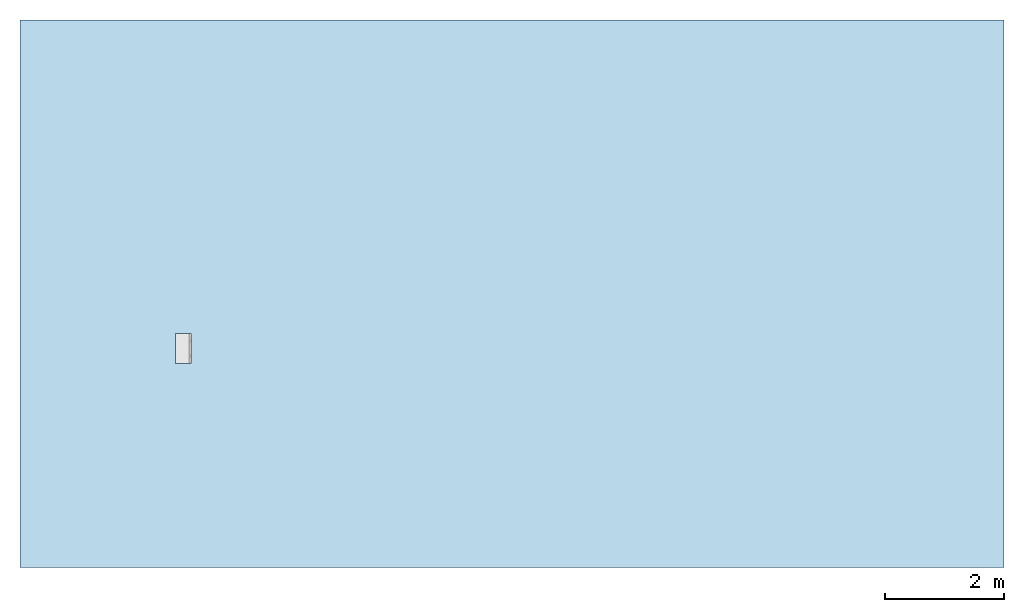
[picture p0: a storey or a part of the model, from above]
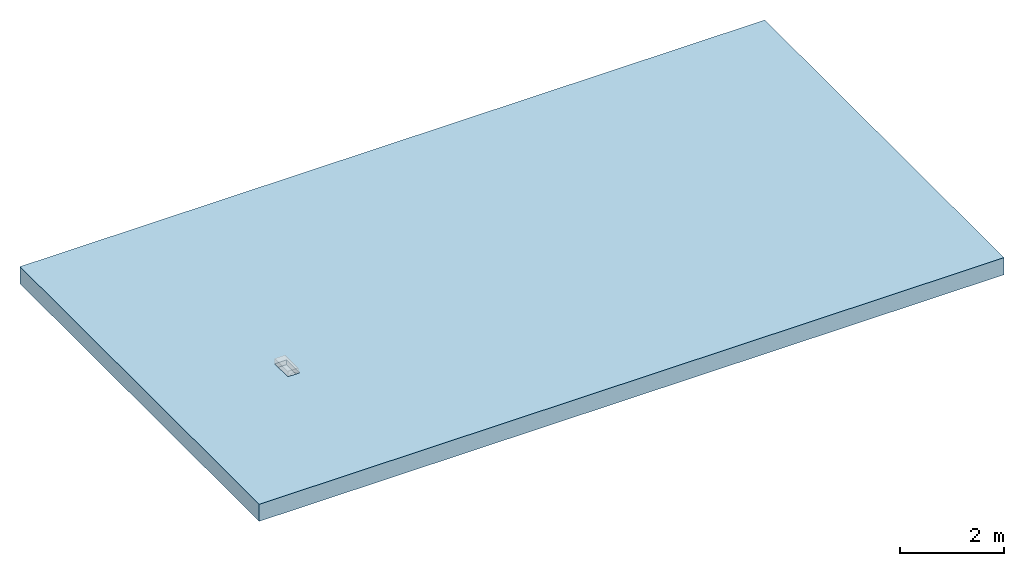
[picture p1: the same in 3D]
Properties of the parts of a building model (IFC2X3)

# File
Description: ViewDefinition [CoordinationView]
File name: T0132 - Channel - 500mm LG - 235mm High.ifc
Time: 2013-09-04T09:02:52
Written by: Autodesk Revit 2013
Made in: 20120221_2030(x64)

# IfcProject, Project Number
LongName: Project Name; Phase: Project Status

# IfcSite, Default
RefLatitude: 42, 21, 30, 344238; RefLongitude: -71, -3, -35, -194702; RefElevation: 0 mm

# IfcBuilding
Pset_BuildingCommon - NumberOfStoreys: 1
Other - Project Address: ## Street City, State Zip; Project Number: Project Number; Client Name: Owner; Project Status: Project Status; Project Issue Date: Issue Date; Project Name: Project Name

# IfcBuildingStorey, Level 1
LongName: Level 1; Elevation: 0 mm
Graphics - Symbol at End 2 Default: yes; Symbol: M_Level Head - Circle: M_Level Head - Circle; Line Pattern: Center; Symbol at End 1 Default: no; Line Weight: 1; Color: 0
Constraints - Elevation Base: 0; Elevation: 0 mm
Identity Data - Name: Level 1; Structural: no; Building Story: yes
Dimensions - Computation Height: 0 mm

# IfcBuildingElementProxy: T0132 - Channel - 500mm LG - 235mm High, Civil-Drainage-Channel-ACO-KerbDrain-KD200:T0132 - Channel - 500mm LG - 235mm High:T0132 - Channel - 500mm LG - 235mm High:308203
In: Level 1
Material: ACO Polymer Concrete.
Phasing - Phase Created: New Construction
Dimensions - Volume: 18537256 mm3; Void Depth.: -110 mm; Void length: 500 mm
Constraints - Level: Level: Level 1; Moves With Nearby Elements: no
Pset_BuildingElementProxyCommon - Reference: T0132 - Channel - 500mm LG - 235mm High
Green Building Properties - Channel Recyclable: Fully recyclable; Access Cover/Frame Recyclable: N/A; Channel Recycled Material Content: 20% minimum; Access Cover/Frame Recycled Material Content: N/A; End Cap Recyclable: N/A; End Cap Recycled Material Content: N/A
Identity Data - Product brochure: http://www.aco.co.uk/download.php?id=120; Type Comments: ACO KerbDrain KD200 half battered kerb unit 235 high 500mm long; OmniClass Number: 23.70.50.24; Assembly Description: Rain Water Drainage; Fax: +44 (0)1462 815895; Price: POA - contact ACO; Address: ACO Business Park, Hitchin Road, Shefford, Bedfordshire, United Kingdom SG17 5TE; OmniClass Title: Rainwater Removal; Model: ACO KerbDrain KD200; Manufacturer: ACO Technologies plc - ACO Water Management Division; Cost: 0; Assembly Code: D2040; e-mail Sales: customersupport@aco.co.uk; Product Page URL: http://www.aco.co.uk/product_detail.php?id=3; Telephone: +44 (0)1462 816666; Maintenance guidelines: http://www.aco.co.uk/download.php?id=120; URL: www.aco.co.uk; Installation guidelines: http://www.aco.co.uk/download.php?id=120; Model Description: Combined kerb and drainage system; Product Code: T0132; e-mail Technical: technical@aco.co.uk
General - TagNumber: 0.000000; SerialNumber: 0.000000
Materials and Finishes - Channel Colour: Grey; Access Cover/Frame Material: N/A; End Cap Colour: N/A; Channel Material: Vienite® Synthetic Resin Concrete; Access Cover/Frame Colour: N/A; End Cap Material: N/A; Access Cover/Frame Finish: N/A
Data - Concrete Surround Volume - Load Class A 15 - D 400 - Concrete Pavement: 0.20m³/m; ACO Hydraulic Design Software: http://www.acodesign.co.uk; Product Dimensions: 500mm x 260mm x 235mm (LxWxH); Product Weight: 40.9 Kg; Channel C.S.A: 0.02m²; Load Class: A 15 - D 400 A 15 - D 400; Invert Depth: 205mm; Product Standard: BS EN 1433:2002, CE marked, Kitemarked; Drainage Slot Width: 50mm; Hydraulic Performance: http://www.aco.co.uk/download.php?id=120; Drainage Slot Intake area: 14592mm²/m; Installation - Concrete Grade: Refer to brochure
Construction - Channelunit_220: no; Closing end cap: no; Blindunit_235: no; Accessunit_235: no; Channelunit_235: yes; Blindunit_220: no; Access Cover: no; Accessunit_220: no
Other - CreatedBy: www.aco.co.uk; Revision: 1

# IfcOpeningElement: Recess
In: Level 1
Constraints - Level: Level: Level 1; Related to Mass: no; Height Offset From Level: 0 mm; Room Bounding: yes
Structural - Structural: no; Enable Analytical Model: no
Phasing - Phase Created: New Construction
Dimensions - Thickness: 400 mm; Perimeter: 51360 mm; Volume: 60573700000 mm3; Area: 151470000 mm2
Construction - Default Thickness: 400 mm; Function: 0
Analytical Properties - Roughness: 1; Absorptance: 0.1
Graphics - Coarse Scale Fill Color: 0
Materials and Finishes - Structural Material: Plant

# IfcSlab: Floor:Generic Floor - 400mm, Floor:Generic Floor - 400mm:193825
In: Level 1
PredefinedType: FLOOR; Material: Plant 400 mm
Constraints - Level: Level: Level 1; Related to Mass: no; Height Offset From Level: 0 mm; Room Bounding: yes
Structural - Structural: no; Enable Analytical Model: no
Phasing - Phase Created: New Construction
Dimensions - Thickness: 400 mm; Perimeter: 51360 mm; Volume: 60573700000 mm3; Area: 151470000 mm2
Pset_SlabCommon - Reference: Generic Floor - 400mm; IsExternal: no; LoadBearing: yes
Construction - Default Thickness: 400 mm; Function: 0
Analytical Properties - Roughness: 1; Absorptance: 0.1
Graphics - Coarse Scale Fill Color: 0
Materials and Finishes - Structural Material: Plant
